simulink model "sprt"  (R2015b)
settings: Solver=FixedStepDiscrete  StartTime=0.0  StopTime=180  FixedStep=0.01  RelTol=1e-3
PreLoadFcn:
  | sinit;
  | 
  | if ~exist('EV3Log')
  |   load LogData;
  | end
  | 
  | Logs.time=EV3Log.time;
  |  nnn=length(EV3Log.signals(1).values);
  |  zzz=zeros(nnn,12);
  |  for i=1:12, zzz(:,i)=EV3Log.signals(i).values; end
  | Logs.signals.values=zzz;
  | Logs.signals.dimensions=12;
undefined symbols (not defined in the file or in its folder): A, B, DiscIntNeverNeededParam, mH, mL, mm, sGD, sGI, sGP, sWD, sWI, sWP, vc1, vc2, vv
libraries: simulink x18

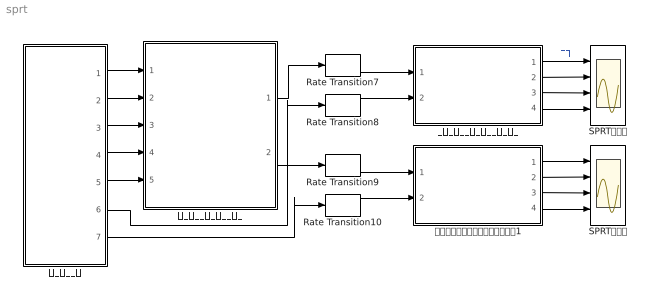
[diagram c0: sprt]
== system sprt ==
  Rate Transition{7..10} (4 alike) : RateTransition  OutPortSampleTime=0.1
  SPRT（右） : Scope  NumInputPorts=4
  SPRT（左） : Scope  NumInputPorts=4
  ロボットから : Subsystem
  右輪コントローラ診断モジュール : Subsystem
  右輪コントローラ診断モジュール1 : Subsystem
  診断用コントローラモデル : Subsystem
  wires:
  右輪コントローラ診断モジュール/3(尤度比(平均減少)) -> SPRT（右）/3
  右輪コントローラ診断モジュール/1(差分) -> SPRT（右）/1  "差分"
  右輪コントローラ診断モジュール/2(尤度比(平均増加)) -> SPRT（右）/2
  右輪コントローラ診断モジュール/4(尤度比(変動増加)) -> SPRT（右）/4
  ロボットから/1(車体角速度) -> 診断用コントローラモデル/1(車体角速度)
  ロボットから/2(右輪回転角度) -> 診断用コントローラモデル/2(右車輪回転角)
  ロボットから/3(左輪回転角度) -> 診断用コントローラモデル/3(左車輪回転角)
  ロボットから/4(右輪角度指示) -> 診断用コントローラモデル/4(姿勢制御前右車輪角度指示値)
  ロボットから/5(左輪角度指示) -> 診断用コントローラモデル/5(姿勢制御前左車輪角度指示値)
  診断用コントローラモデル/1(右コントローラモデル出力) -> Rate Transition7/1
  診断用コントローラモデル/2("左コントローラモデル出力 ") -> Rate Transition9/1
  右輪コントローラ診断モジュール1/1(差分) -> SPRT（左）/1
  右輪コントローラ診断モジュール1/4(尤度比(変動増加)) -> SPRT（左）/4
  右輪コントローラ診断モジュール1/3(尤度比(平均減少)) -> SPRT（左）/3
  右輪コントローラ診断モジュール1/2(尤度比(平均増加)) -> SPRT（左）/2
  ロボットから/6(右輪コントローラ出力) -> Rate Transition8/1
  ロボットから/7(左輪コントローラ出力) -> Rate Transition10/1
  Rate Transition7/1 -> 右輪コントローラ診断モジュール/1(診断モデル出力)
  Rate Transition8/1 -> 右輪コントローラ診断モジュール/2(EV3出力)
  Rate Transition9/1 -> 右輪コントローラ診断モジュール1/1(診断モデル出力)
  Rate Transition10/1 -> 右輪コントローラ診断モジュール1/2(EV3出力)

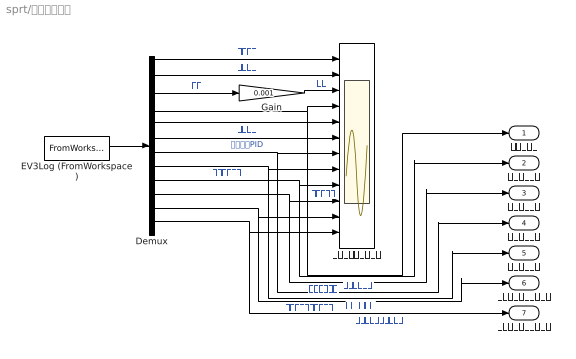
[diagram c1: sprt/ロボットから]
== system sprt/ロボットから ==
  Demux : Demux  Outputs=12
  EV3Log (FromWorkspace) : FromWorkspace  VariableName=Logs  SampleTime=0.01  OutputAfterFinalValue=Setting to zero
  Gain : Gain  Gain=0.001
  ロボット出力データ : Scope  NumInputPorts=12
  車体角速度 : Outport
  右輪回転角度 : Outport  Port=2
  左輪回転角度 : Outport  Port=3
  右輪角度指示 : Outport  Port=4
  左輪角度指示 : Outport  Port=5
  右輪コントローラ出力 : Outport  Port=6
  左輪コントローラ出力 : Outport  Port=7
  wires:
  Demux/1 -> ロボット出力データ/1  "前後指示"
  Demux/2 -> ロボット出力データ/2  "左右指示"
  EV3Log (FromWorkspace)/1 -> Demux/1
  Gain/1 -> ロボット出力データ/3  "時間"
  Demux/3 -> Gain/1  "時間"
  Demux/4 -> 車体角速度/1, ロボット出力データ/4  "車体角速度"
  Demux/5 -> ロボット出力データ/5  "車体角度"
  Demux/6 -> ロボット出力データ/6  "ジャイロPID"
  Demux/7 -> 右輪角度指示/1, ロボット出力データ/7  "右輪角度指示"
  Demux/8 -> 左輪角度指示/1, ロボット出力データ/8  "左輪角度指示"
  Demux/9 -> 右輪回転角度/1, ロボット出力データ/9  "右輪回転角度"
  Demux/10 -> 左輪回転角度/1, ロボット出力データ/10  "左輪回転角度"
  Demux/11 -> 右輪コントローラ出力/1, ロボット出力データ/11  "右輪コントローラ出力"
  Demux/12 -> 左輪コントローラ出力/1, ロボット出力データ/12  "左輪コントローラ出力"

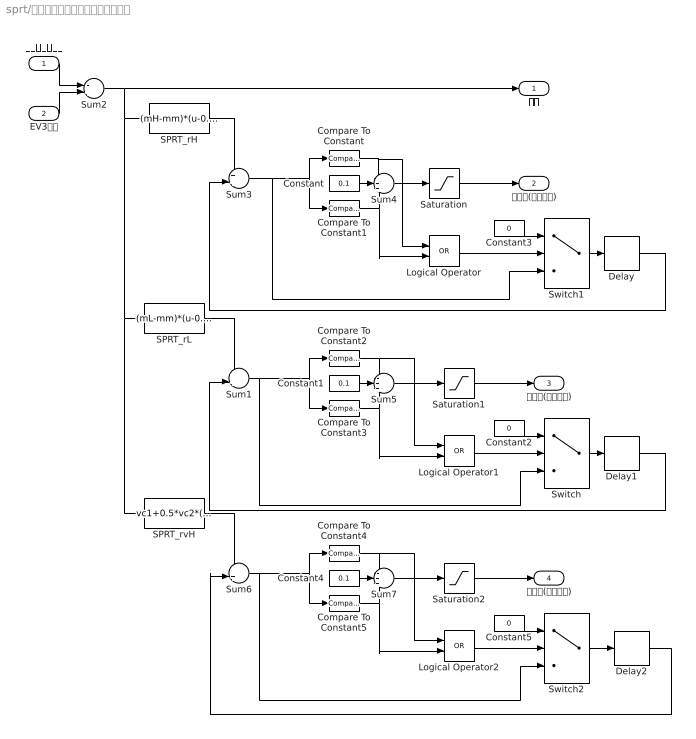
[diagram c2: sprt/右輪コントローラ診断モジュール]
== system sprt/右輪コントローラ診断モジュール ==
  診断モデル出力 : Inport
  EV3出力 : Inport  Port=2
  Compare To Constant : simulink/Logic and Bit Operations/Compare To Constant  relop=<=  const=B  OutDataTypeStr=uint8
  Compare To Constant1 : simulink/Logic and Bit Operations/Compare To Constant  relop=>=  const=A  OutDataTypeStr=uint8
  Compare To Constant2 : simulink/Logic and Bit Operations/Compare To Constant  relop=<=  const=B  OutDataTypeStr=uint8
  Compare To Constant3 : simulink/Logic and Bit Operations/Compare To Constant  relop=>=  const=A  OutDataTypeStr=uint8
  Compare To Constant4 : simulink/Logic and Bit Operations/Compare To Constant  relop=<=  const=B  OutDataTypeStr=uint8
  Compare To Constant5 : simulink/Logic and Bit Operations/Compare To Constant  relop=>=  const=A  OutDataTypeStr=uint8
  Constant : Constant  Value=0.1
  Constant1 : Constant  Value=0.1
  Constant2 : Constant  Value=0
  Constant3 : Constant  Value=0
  Constant4 : Constant  Value=0.1
  Constant5 : Constant  Value=0
  Delay : Delay  DelayLength=1
  Delay1 : Delay  DelayLength=1
  Delay2 : Delay  DelayLength=1
  Logical Operator : Logic  Operator=OR  AllPortsSameDT=off  OutDataTypeStr=boolean
  Logical Operator1 : Logic  Operator=OR  AllPortsSameDT=off  OutDataTypeStr=boolean
  Logical Operator2 : Logic  Operator=OR  AllPortsSameDT=off  OutDataTypeStr=boolean
  SPRT_rH : Fcn  Expr=(mH-mm)*(u-0.5*(mm+mH))/vv
  SPRT_rL : Fcn  Expr=(mL-mm)*(u-0.5*(mm+mL))/vv
  SPRT_rvH : Fcn  Expr=vc1+0.5*vc2*(u-mm)^2
  Saturation : Saturate  UpperLimit=1  LowerLimit=0
  Saturation1 : Saturate  UpperLimit=1  LowerLimit=0
  Saturation2 : Saturate  UpperLimit=1  LowerLimit=0
  Sum1 : Sum  Inputs=++|
  Sum2 : Sum  Inputs=-+
  Sum3 : Sum  Inputs=++|
  Sum4 : Sum  Inputs=-++
  Sum5 : Sum  Inputs=-++
  Sum6 : Sum  Inputs=++|
  Sum7 : Sum  Inputs=-++
  Switch : Switch  Criteria=u2 > Threshold
  Switch1 : Switch  Criteria=u2 > Threshold
  Switch2 : Switch  Criteria=u2 > Threshold
  差分 : Outport
  尤度比(平均増加) : Outport  Port=2
  尤度比(平均減少) : Outport  Port=3
  尤度比(変動増加) : Outport  Port=4
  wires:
  Sum2/1 -> SPRT_rvH/1, SPRT_rL/1, SPRT_rH/1, 差分/1
  診断モデル出力/1 -> Sum2/1
  EV3出力/1 -> Sum2/2
  Switch1/1 -> Delay/1
  SPRT_rH/1 -> Sum3/1
  SPRT_rL/1 -> Sum1/1
  Sum1/1 -> Switch/3, Compare To Constant2/1, Compare To Constant3/1
  Compare To Constant/1 -> Logical Operator/1, Sum4/1
  Constant/1 -> Sum4/2
  Compare To Constant1/1 -> Logical Operator/2, Sum4/3
  Sum4/1 -> Saturation/1
  Switch/1 -> Delay1/1
  Constant1/1 -> Sum5/2
  Sum5/1 -> Saturation1/1
  Saturation/1 -> 尤度比(平均増加)/1
  Saturation1/1 -> 尤度比(平均減少)/1
  Compare To Constant2/1 -> Logical Operator1/1, Sum5/1
  Compare To Constant3/1 -> Logical Operator1/2, Sum5/3
  Logical Operator1/1 -> Switch/2
  Constant2/1 -> Switch/1
  Sum3/1 -> Switch1/3, Compare To Constant/1, Compare To Constant1/1
  Logical Operator/1 -> Switch1/2
  Constant3/1 -> Switch1/1
  SPRT_rvH/1 -> Sum6/1
  Sum6/1 -> Switch2/3, Compare To Constant4/1, Compare To Constant5/1
  Switch2/1 -> Delay2/1
  Constant4/1 -> Sum7/2
  Sum7/1 -> Saturation2/1
  Saturation2/1 -> 尤度比(変動増加)/1
  Compare To Constant4/1 -> Logical Operator2/1, Sum7/1
  Compare To Constant5/1 -> Logical Operator2/2, Sum7/3
  Logical Operator2/1 -> Switch2/2
  Constant5/1 -> Switch2/1
  Delay/1 -> Sum3/2
  Delay1/1 -> Sum1/2
  Delay2/1 -> Sum6/2

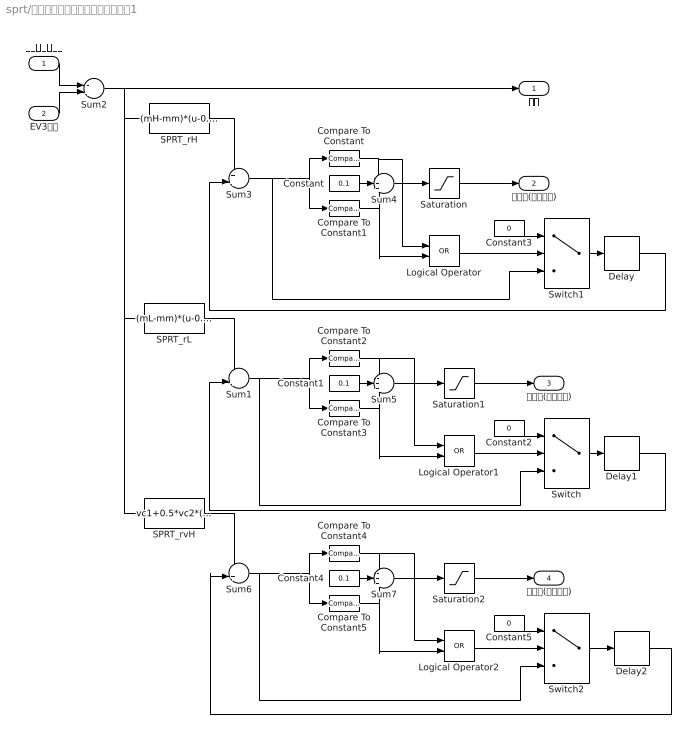
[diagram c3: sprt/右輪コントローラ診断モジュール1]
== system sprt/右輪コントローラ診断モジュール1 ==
  診断モデル出力 : Inport
  EV3出力 : Inport  Port=2
  Compare To Constant : simulink/Logic and Bit Operations/Compare To Constant  relop=<=  const=B  OutDataTypeStr=uint8
  Compare To Constant1 : simulink/Logic and Bit Operations/Compare To Constant  relop=>=  const=A  OutDataTypeStr=uint8
  Compare To Constant2 : simulink/Logic and Bit Operations/Compare To Constant  relop=<=  const=B  OutDataTypeStr=uint8
  Compare To Constant3 : simulink/Logic and Bit Operations/Compare To Constant  relop=>=  const=A  OutDataTypeStr=uint8
  Compare To Constant4 : simulink/Logic and Bit Operations/Compare To Constant  relop=<=  const=B  OutDataTypeStr=uint8
  Compare To Constant5 : simulink/Logic and Bit Operations/Compare To Constant  relop=>=  const=A  OutDataTypeStr=uint8
  Constant : Constant  Value=0.1
  Constant1 : Constant  Value=0.1
  Constant2 : Constant  Value=0
  Constant3 : Constant  Value=0
  Constant4 : Constant  Value=0.1
  Constant5 : Constant  Value=0
  Delay : Delay  DelayLength=1
  Delay1 : Delay  DelayLength=1
  Delay2 : Delay  DelayLength=1
  Logical Operator : Logic  Operator=OR  AllPortsSameDT=off  OutDataTypeStr=boolean
  Logical Operator1 : Logic  Operator=OR  AllPortsSameDT=off  OutDataTypeStr=boolean
  Logical Operator2 : Logic  Operator=OR  AllPortsSameDT=off  OutDataTypeStr=boolean
  SPRT_rH : Fcn  Expr=(mH-mm)*(u-0.5*(mm+mH))/vv
  SPRT_rL : Fcn  Expr=(mL-mm)*(u-0.5*(mm+mL))/vv
  SPRT_rvH : Fcn  Expr=vc1+0.5*vc2*(u-mm)^2
  Saturation : Saturate  UpperLimit=1  LowerLimit=0
  Saturation1 : Saturate  UpperLimit=1  LowerLimit=0
  Saturation2 : Saturate  UpperLimit=1  LowerLimit=0
  Sum1 : Sum  Inputs=++|
  Sum2 : Sum  Inputs=-+
  Sum3 : Sum  Inputs=++|
  Sum4 : Sum  Inputs=-++
  Sum5 : Sum  Inputs=-++
  Sum6 : Sum  Inputs=++|
  Sum7 : Sum  Inputs=-++
  Switch : Switch  Criteria=u2 > Threshold
  Switch1 : Switch  Criteria=u2 > Threshold
  Switch2 : Switch  Criteria=u2 > Threshold
  差分 : Outport
  尤度比(平均増加) : Outport  Port=2
  尤度比(平均減少) : Outport  Port=3
  尤度比(変動増加) : Outport  Port=4
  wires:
  Sum2/1 -> SPRT_rvH/1, SPRT_rL/1, SPRT_rH/1, 差分/1
  診断モデル出力/1 -> Sum2/1
  EV3出力/1 -> Sum2/2
  Switch1/1 -> Delay/1
  SPRT_rH/1 -> Sum3/1
  SPRT_rL/1 -> Sum1/1
  Sum1/1 -> Switch/3, Compare To Constant2/1, Compare To Constant3/1
  Compare To Constant/1 -> Logical Operator/1, Sum4/1
  Constant/1 -> Sum4/2
  Compare To Constant1/1 -> Logical Operator/2, Sum4/3
  Sum4/1 -> Saturation/1
  Switch/1 -> Delay1/1
  Constant1/1 -> Sum5/2
  Sum5/1 -> Saturation1/1
  Saturation/1 -> 尤度比(平均増加)/1
  Saturation1/1 -> 尤度比(平均減少)/1
  Compare To Constant2/1 -> Logical Operator1/1, Sum5/1
  Compare To Constant3/1 -> Logical Operator1/2, Sum5/3
  Logical Operator1/1 -> Switch/2
  Constant2/1 -> Switch/1
  Sum3/1 -> Switch1/3, Compare To Constant/1, Compare To Constant1/1
  Logical Operator/1 -> Switch1/2
  Constant3/1 -> Switch1/1
  SPRT_rvH/1 -> Sum6/1
  Sum6/1 -> Switch2/3, Compare To Constant4/1, Compare To Constant5/1
  Switch2/1 -> Delay2/1
  Constant4/1 -> Sum7/2
  Sum7/1 -> Saturation2/1
  Saturation2/1 -> 尤度比(変動増加)/1
  Compare To Constant4/1 -> Logical Operator2/1, Sum7/1
  Compare To Constant5/1 -> Logical Operator2/2, Sum7/3
  Logical Operator2/1 -> Switch2/2
  Constant5/1 -> Switch2/1
  Delay/1 -> Sum3/2
  Delay1/1 -> Sum1/2
  Delay2/1 -> Sum6/2

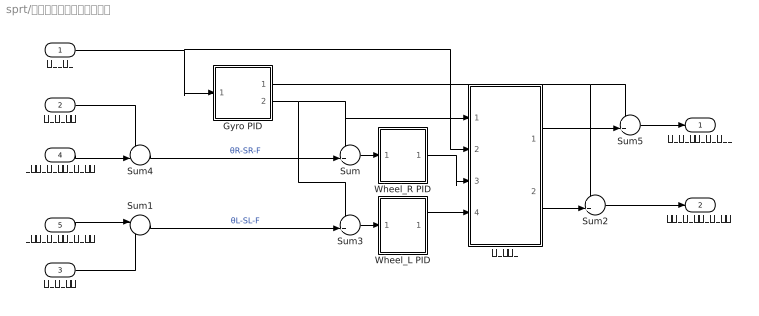
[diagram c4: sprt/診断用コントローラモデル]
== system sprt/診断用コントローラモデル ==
  車体角速度 : Inport
  右車輪回転角 : Inport  Port=2
  左車輪回転角 : Inport  Port=3
  姿勢制御前右車輪角度指示値 : Inport  Port=4
  姿勢制御前左車輪角度指示値 : Inport  Port=5
  Gyro PID : Subsystem
  Sum{,2..3,5} (4 alike) : Sum  Inputs=++|
  Sum1 : Sum  Inputs=|-+
  Sum4 : Sum  Inputs=+-|
  Wheel_L PID : Subsystem
  Wheel_R PID : Subsystem
  ルール制御 : Subsystem
  右コントローラモデル出力 : Outport
  "左コントローラモデル出力 " : Outport  Port=2
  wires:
  ルール制御/2(左補正値) -> Sum2/2
  ルール制御/1(右補正値) -> Sum5/2
  Sum/1 -> Wheel_R PID/1(Ang)
  車体角速度/1 -> Gyro PID/1(GyroD), ルール制御/2(角速度)
  Gyro PID/1(Req) -> Sum5/1, Sum2/1
  Gyro PID/2(Theta) -> ルール制御/1(角度), Sum/1, Sum3/1
  Sum1/1 -> Sum3/2  "θL-SL-F"
  姿勢制御前右車輪角度指示値/1 -> Sum4/2
  右車輪回転角/1 -> Sum4/1
  左車輪回転角/1 -> Sum1/2
  Sum4/1 -> Sum/2  "θR-SR-F"
  姿勢制御前左車輪角度指示値/1 -> Sum1/1
  Sum3/1 -> Wheel_L PID/1(Ang)
  Wheel_L PID/1(Req) -> ルール制御/4(左要求値)
  Wheel_R PID/1(Req) -> ルール制御/3(右要求値)
  Sum5/1 -> 右コントローラモデル出力/1
  Sum2/1 -> "左コントローラモデル出力 "/1

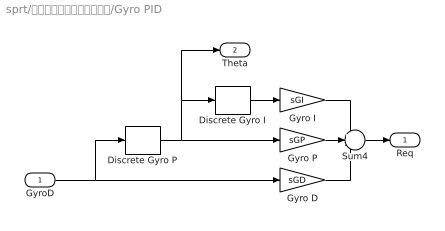
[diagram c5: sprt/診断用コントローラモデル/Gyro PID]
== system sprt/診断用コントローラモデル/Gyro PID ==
  GyroD : Inport
  Discrete Gyro I : DiscreteIntegrator  InitialConditionSetting=State (most efficient)  SampleTime=-1  ICPrevOutput=DiscIntNeverNeededParam  ICPrevScaledInput=DiscIntNeverNeededParam
  Discrete Gyro P : DiscreteIntegrator  InitialConditionSetting=State (most efficient)  SampleTime=-1  ICPrevOutput=DiscIntNeverNeededParam  ICPrevScaledInput=DiscIntNeverNeededParam
  Gyro D : Gain  Gain=sGD
  Gyro I : Gain  Gain=sGI
  Gyro P : Gain  Gain=sGP
  Sum4 : Sum  Inputs=3
  Req : Outport
  Theta : Outport  Port=2
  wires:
  Gyro I/1 -> Sum4/1
  Discrete Gyro I/1 -> Gyro I/1
  Gyro D/1 -> Sum4/3
  Gyro P/1 -> Sum4/2
  GyroD/1 -> Discrete Gyro P/1, Gyro D/1
  Discrete Gyro P/1 -> Theta/1, Discrete Gyro I/1, Gyro P/1
  Sum4/1 -> Req/1

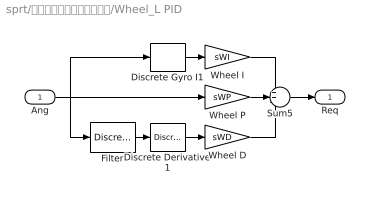
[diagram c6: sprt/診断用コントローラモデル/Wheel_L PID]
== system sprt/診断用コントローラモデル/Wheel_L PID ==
  Ang : Inport
  Discrete Derivative1 : simulink/Discrete/Discrete Derivative  gainval=1.0  ICPrevScaledInput=0.0  InputProcessing=Inherited  OutMin=[]  OutMax=[]  OutDataType=fixdt(1, 16)  OutScaling=2^-10  DoSatur=off
  Discrete Gyro I1 : DiscreteIntegrator  InitialConditionSetting=State (most efficient)  SampleTime=-1  ICPrevOutput=DiscIntNeverNeededParam  ICPrevScaledInput=DiscIntNeverNeededParam
  Filter : DiscreteFilter  Numerator=[0.2]  Denominator=[1 -0.8]
  Sum5 : Sum  Inputs=3
  Wheel D : Gain  Gain=sWD
  Wheel I : Gain  Gain=sWI
  Wheel P : Gain  Gain=sWP
  Req : Outport
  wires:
  Ang/1 -> Wheel P/1, Filter/1, Discrete Gyro I1/1
  Filter/1 -> Discrete Derivative1/1
  Wheel I/1 -> Sum5/1
  Wheel D/1 -> Sum5/3
  Wheel P/1 -> Sum5/2
  Discrete Gyro I1/1 -> Wheel I/1
  Discrete Derivative1/1 -> Wheel D/1
  Sum5/1 -> Req/1

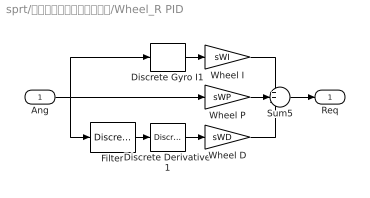
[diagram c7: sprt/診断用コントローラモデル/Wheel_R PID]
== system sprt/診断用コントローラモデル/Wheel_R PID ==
  Ang : Inport
  Discrete Derivative1 : simulink/Discrete/Discrete Derivative  gainval=1.0  ICPrevScaledInput=0.0  InputProcessing=Inherited  OutMin=[]  OutMax=[]  OutDataType=fixdt(1, 16)  OutScaling=2^-10  DoSatur=off
  Discrete Gyro I1 : DiscreteIntegrator  InitialConditionSetting=State (most efficient)  SampleTime=-1  ICPrevOutput=DiscIntNeverNeededParam  ICPrevScaledInput=DiscIntNeverNeededParam
  Filter : DiscreteFilter  Numerator=[0.2]  Denominator=[1 -0.8]
  Sum5 : Sum  Inputs=3
  Wheel D : Gain  Gain=sWD
  Wheel I : Gain  Gain=sWI
  Wheel P : Gain  Gain=sWP
  Req : Outport
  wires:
  Ang/1 -> Wheel P/1, Filter/1, Discrete Gyro I1/1
  Filter/1 -> Discrete Derivative1/1
  Wheel I/1 -> Sum5/1
  Wheel D/1 -> Sum5/3
  Wheel P/1 -> Sum5/2
  Discrete Gyro I1/1 -> Wheel I/1
  Discrete Derivative1/1 -> Wheel D/1
  Sum5/1 -> Req/1

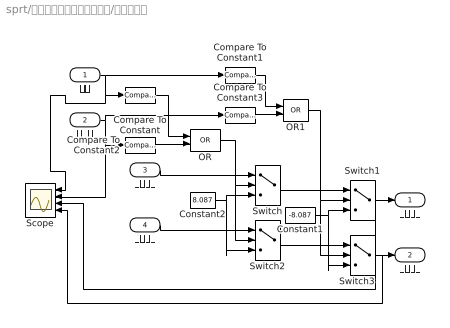
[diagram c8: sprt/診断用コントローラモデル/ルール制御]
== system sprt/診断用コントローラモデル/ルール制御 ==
  角度 : Inport
  角速度 : Inport  Port=2
  右要求値 : Inport  Port=3
  左要求値 : Inport  Port=4
  Compare To Constant : simulink/Logic and Bit Operations/Compare To Constant  relop=<  const=13  OutDataTypeStr=boolean
  Compare To Constant1 : simulink/Logic and Bit Operations/Compare To Constant  relop=>  const=-13  OutDataTypeStr=boolean
  Compare To Constant2 : simulink/Logic and Bit Operations/Compare To Constant  relop=<  const=100  OutDataTypeStr=boolean
  Compare To Constant3 : simulink/Logic and Bit Operations/Compare To Constant  relop=>  const=-100  OutDataTypeStr=boolean
  Constant1 : Constant  Value=-8.087
  Constant2 : Constant  Value=8.087
  OR : Logic  Operator=OR  IconShape=distinctive  AllPortsSameDT=off  OutDataTypeStr=boolean
  OR1 : Logic  Operator=OR  IconShape=distinctive  AllPortsSameDT=off  OutDataTypeStr=boolean
  Scope : Scope  NumInputPorts=4
  Switch : Switch  Criteria=u2 ~= 0  Threshold=30
  Switch1 : Switch  Criteria=u2 ~= 0  Threshold=-30
  Switch2 : Switch  Criteria=u2 ~= 0  Threshold=30
  Switch3 : Switch  Criteria=u2 ~= 0  Threshold=-30
  右補正値 : Outport
  左補正値 : Outport  Port=2
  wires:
  Switch3/1 -> Scope/4, 左補正値/1
  Switch1/1 -> Scope/3, 右補正値/1
  Constant2/1 -> Switch2/3, Switch/3
  右要求値/1 -> Switch/1
  Switch/1 -> Switch1/1
  左要求値/1 -> Switch2/1
  Constant1/1 -> Switch1/3, Switch3/3
  Switch2/1 -> Switch3/1
  OR/1 -> Switch2/2, Switch/2
  OR1/1 -> Switch1/2, Switch3/2
  角度/1 -> Scope/1, Compare To Constant/1, Compare To Constant1/1
  角速度/1 -> Compare To Constant3/1, Scope/2, Compare To Constant2/1
  Compare To Constant/1 -> OR/1
  Compare To Constant2/1 -> OR/2
  Compare To Constant1/1 -> OR1/1
  Compare To Constant3/1 -> OR1/2
